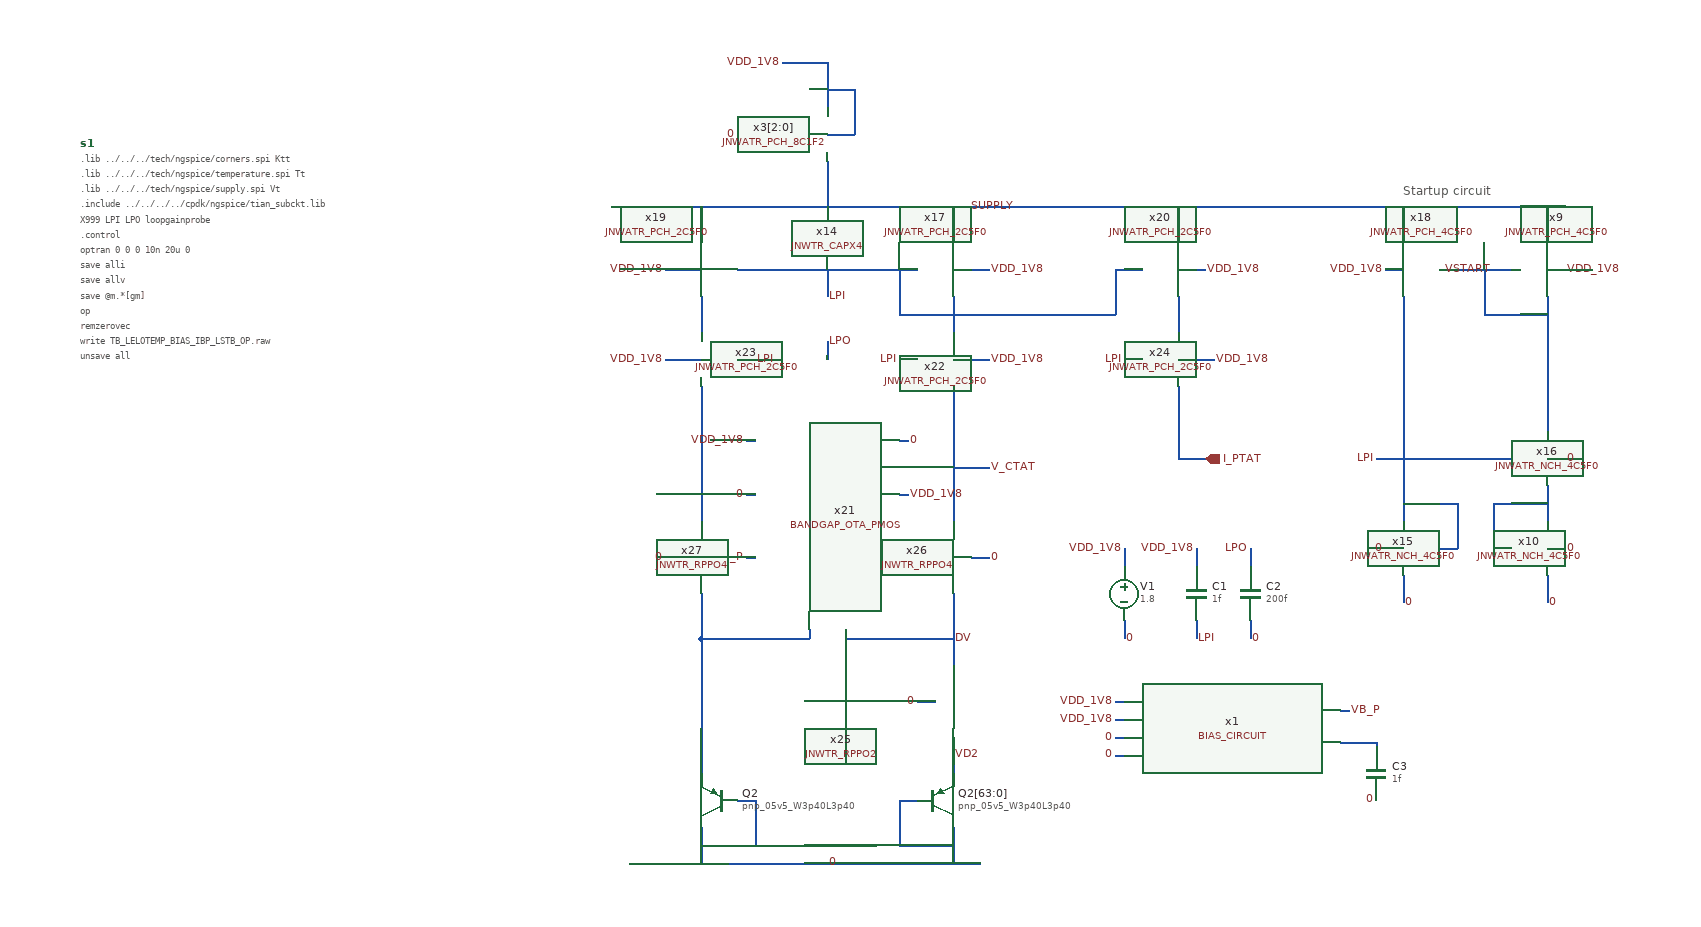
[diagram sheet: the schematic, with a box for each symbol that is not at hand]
v {xschem version=3.4.7 file_version=1.2}
G {}
K {}
V {}
S {}
E {}
B 2 790 -340 1590 60 {flags=graph

y2=71.09439
ypos1=0
ypos2=2
divy=5
subdivy=1
unity=1


divx=5
subdivx=8
xlabmag=1.0
ylabmag=1.0
node=re(lg_mag)
color=5
dataset=-1
unitx=1
logx=1
logy=0
sim_type=ac

y1=-47.074905
autoload=1
x1=2.1288585
x2=8.6859343}
B 2 790 70 1590 470 {flags=graph


ypos1=0
ypos2=2
divy=5
subdivy=4
unity=1

x2=8.6859343
divx=5
subdivx=8
xlabmag=1.0
ylabmag=1.0


dataset=-1
unitx=1
logx=1
logy=0
sim_type=ac
x1=2.1288585
y1=-242.0359
y2=16.778858
color=4
node=re(lg_phase)
autoload=0
rawfile=$netlist_dir/TB_LELOTEMP_BIAS_IBP_LSTB.raw}
T {Startup circuit} 520 -230 0 0 0.4 0.4 {}
N 210 180 210 200 {
lab=VDD_1V8}
N -220 -130 -20 -130 {lab=LPI}
N -140 270 -140 280 {lab=#net1}
N -260 280 -140 280 {lab=#net1}
N -100 270 -100 280 {lab=DV}
N 20 390 20 430 {lab=VD2}
N -260 280 -260 430 {lab=#net1}
N -40 510 20 510 {lab=0}
N -40 460 -40 510 {lab=0}
N -40 460 -20 460 {lab=0}
N 270 -130 300 -130 {lab=VDD_1V8}
N 200 -130 230 -130 {lab=LPI}
N 270 0 270 80 {lab=I_PTAT}
N -210 120 -200 120 {lab=0}
N -40 120 -30 120 {lab=VDD_1V8}
N 20 -130 60 -130 {lab=VDD_1V8}
N -300 -130 -260 -130 {lab=VDD_1V8}
N -260 -200 -260 -160 {lab=SUPPLY}
N 20 -200 20 -160 {lab=SUPPLY}
N 270 -200 270 -160 {lab=SUPPLY}
N 270 80 300 80 {lab=I_PTAT}
N 20 90 60 90 {lab=V_CTAT}
N -40 -130 -40 -80 {lab=LPI}
N 200 -130 200 -80 {lab=LPI}
N -120 -250 -120 -200 {lab=SUPPLY}
N -220 -280 -160 -280 {lab=0}
N -120 -360 -120 -310 {lab=VDD_1V8}
N -170 -360 -120 -360 {lab=VDD_1V8}
N -40 60 -30 60 {lab=0}
N -120 -280 -90 -280 {lab=VDD_1V8}
N -90 -330 -90 -280 {lab=VDD_1V8}
N -120 -330 -90 -330 {lab=VDD_1V8}
N -210 60 -200 60 {lab=VDD_1V8}
N -210 190 -200 190 {lab=VB_P}
N -300 -30 -260 -30 {lab=VDD_1V8}
N -220 -30 -200 -30 {lab=LPI}
N -260 -100 -260 -60 {lab=#net2}
N 20 -100 20 -60 {lab=#net3}
N 20 -30 60 -30 {lab=VDD_1V8}
N -40 -30 -20 -30 {lab=LPI}
N 270 -30 310 -30 {lab=VDD_1V8}
N 270 -100 270 -60 {lab=#net4}
N 210 -30 230 -30 {lab=LPI}
N -260 510 -200 510 {lab=0}
N -200 460 -200 510 {lab=0}
N -220 460 -200 460 {lab=0}
N -260 490 -260 530 {lab=0}
N 20 490 20 530 {lab=0}
N -40 -80 200 -80 {lab=LPI}
N 680 -200 680 -160 {lab=SUPPLY}
N 520 -200 520 -160 {lab=SUPPLY}
N 500 -130 520 -130 {lab=VDD_1V8}
N 680 -130 700 -130 {lab=VDD_1V8}
N 680 80 700 80 {lab=0}
N 560 -130 640 -130 {lab=VSTART}
N 610 -130 610 -80 {lab=VSTART}
N 610 -80 680 -80 {lab=VSTART}
N 620 180 640 180 {lab=#net5}
N 680 180 700 180 {lab=0}
N 620 130 620 180 {lab=#net5}
N 680 110 680 150 {lab=#net5}
N 620 130 680 130 {lab=#net5}
N 680 210 680 240 {lab=0}
N 560 180 580 180 {lab=LPI}
N 500 180 520 180 {lab=0}
N 580 130 580 180 {lab=LPI}
N 520 130 580 130 {lab=LPI}
N 520 210 520 240 {lab=0}
N 520 -100 520 150 {lab=LPI}
N 520 80 640 80 {lab=LPI}
N 680 -100 680 50 {lab=VSTART}
N 490 80 520 80 {lab=LPI}
N -100 280 20 280 {lab=DV}
N -220 -280 -160 -280 {lab=0}
N -20 350 0 350 {lab=0}
N -260 0 -260 110 {lab=#net6}
N 20 0 20 80 {lab=V_CTAT}
N 20 80 20 100 {lab=V_CTAT}
N 20 100 20 150 {lab=V_CTAT}
N 20 230 20 310 {lab=DV}
N -260 110 -260 150 {lab=#net6}
N -260 230 -260 280 {lab=#net1}
N 40 190 60 190 {lab=0}
N -300 190 -280 190 {lab=0}
N -360 -200 700 -200 {lab=SUPPLY}
N -340 530 50 530 {lab=0}
N 200 350 210 350 {lab=VDD_1V8}
N 200 370 210 370 {lab=VDD_1V8}
N 200 390 210 390 {lab=0}
N 200 410 210 410 {lab=0}
N 450 360 460 360 {lab=VB_P}
N 450 395 490 395 {lab=#net7}
N 490 395 490 400 {lab=#net7}
N -120 -50 -120 -30 {lab=LPO}
N -120 -130 -120 -100 {lab=LPI}
N 210 260 210 280 {lab=0}
N 350 180 350 200 {lab=LPO}
N 290 180 290 200 {lab=VDD_1V8}
N 290 260 290 280 {lab=LPI}
N 350 260 350 280 {lab=0}
C {devices/code_shown.sym} -949.3514969502943 -270 0 0 {name=s1 only_toplevel=false value="

.lib "../../../tech/ngspice/corners.spi" Ktt
.lib "../../../tech/ngspice/temperature.spi" Tt
.lib "../../../tech/ngspice/supply.spi" Vt
.include ../../../../cpdk/ngspice/tian_subckt.lib
X999 LPI LPO loopgainprobe

.control
optran 0 0 0 10n 20u 0
save alli
save allv
save @m.*[gm]
op
remzerovec
write TB_LELOTEMP_BIAS_IBP_LSTB_OP.raw
unsave all

save allv
save i(v1) i(v2)
* Set voltage AC to 1
ac dec 50 100 1G
* Set Current to 1
alter i.X999.Ii acmag=1
alter v.X999.Vi acmag=0
ac dec 50 100 1G
let lg_mag = db(tian_loop())
let lg_phase = 180*cph(-tian_loop())/pi
remzerovec
write TB_LELOTEMP_BIAS_IBP_LSTB.raw

meas ac gm_db find lg_mag when lg_phase=0
meas ac pm_deg find lg_phase when lg_mag=0
meas ac f3db when lg_phase=135
meas ac ug when lg_mag=0
meas ac lf_gain find lg_mag at=1k
remzerovec
write TB_LELOTEMP_BIAS_IBP_LSTB_meas.raw
exit
.endc
.end

"}
C {devices/vsource.sym} 210 230 0 0 {name=V1 value=1.8 savecurrent=false}
C {devices/lab_wire.sym} 210 180 0 0 {name=p6 sig_type=std_logic lab=VDD_1V8
value=1.8}
C {devices/capa.sym} 290 230 0 0 {name=C1
m=1
value=1f
footprint=1206
device="ceramic capacitor"}
C {devices/lab_wire.sym} 290 180 0 0 {name=p11 sig_type=std_logic lab=VDD_1V8}
C {devices/lab_wire.sym} 290 280 2 0 {name=p12 sig_type=std_logic lab=LPI}
C {devices/lab_wire.sym} -120 -100 2 0 {name=p1 sig_type=std_logic lab=LPI}
C {devices/lab_wire.sym} 350 180 0 0 {name=p2 sig_type=std_logic lab=LPO}
C {devices/capa.sym} 350 230 0 0 {name=C2
m=1
value=200f
footprint=1206
device="ceramic capacitor"}
C {devices/lab_wire.sym} 210 280 2 0 {name=p13 sig_type=std_logic lab=0
value=1.8}
C {devices/lab_wire.sym} 350 280 2 0 {name=p14 sig_type=std_logic lab=0
value=1.8}
C {devices/lab_pin.sym} 20 410 0 1 {name=p29 sig_type=std_logic lab=VD2}
C {devices/lab_pin.sym} 20 280 0 1 {name=p30 sig_type=std_logic lab=DV}
C {devices/opin.sym} 300 80 0 0 {name=p31 lab=I_PTAT}
C {sky130_fd_pr/pnp_05v5.sym} 0 460 0 0 {name=Q2[63:0]
model=pnp_05v5_W3p40L3p40
m=1
spiceprefix=X
}
C {devices/lab_wire.sym} -30 120 0 1 {name=p38 sig_type=std_logic lab=VDD_1V8}
C {devices/lab_wire.sym} -300 -130 0 0 {name=p39 sig_type=std_logic lab=VDD_1V8}
C {devices/lab_wire.sym} 60 -130 0 1 {name=p40 sig_type=std_logic lab=VDD_1V8}
C {devices/lab_wire.sym} 300 -130 0 1 {name=p41 sig_type=std_logic lab=VDD_1V8}
C {devices/lab_wire.sym} -210 190 0 0 {name=p45 sig_type=std_logic lab=VB_P}
C {devices/lab_wire.sym} -300 -30 0 0 {name=p46 sig_type=std_logic lab=VDD_1V8}
C {devices/lab_wire.sym} 60 -30 0 1 {name=p48 sig_type=std_logic lab=VDD_1V8}
C {devices/lab_wire.sym} 310 -30 0 1 {name=p50 sig_type=std_logic lab=VDD_1V8}
C {sky130_fd_pr/pnp_05v5.sym} -240 460 0 1 {name=Q2
model=pnp_05v5_W3p40L3p40
m=1
spiceprefix=X
}
C {JNW_ATR_SKY130A/JNWATR_NCH_4C5F0.sym} 640 80 0 0 {name=x16}
C {JNW_ATR_SKY130A/JNWATR_PCH_4C5F0.sym} 560 -130 0 1 {name=x18}
C {devices/lab_wire.sym} 500 -130 0 0 {name=p51 sig_type=std_logic lab=VDD_1V8}
C {devices/lab_wire.sym} 700 -130 0 1 {name=p52 sig_type=std_logic lab=VDD_1V8}
C {JNW_ATR_SKY130A/JNWATR_PCH_4C5F0.sym} 640 -130 0 0 {name=x9}
C {JNW_ATR_SKY130A/JNWATR_NCH_4C5F0.sym} 640 180 0 0 {name=x10}
C {JNW_ATR_SKY130A/JNWATR_NCH_4C5F0.sym} 560 180 0 1 {name=x15}
C {JNW_TR_SKY130A/JNWTR_CAPX4.sym} -120 -140 0 0 {name=x14 }
C {devices/lab_wire.sym} 620 -130 0 0 {name=p61 sig_type=std_logic lab=VSTART}
C {LELO_GR03_SKY130A/BANDGAP_OTA_PMOS.sym} -100 120 1 1 {name=x21}
C {JNW_ATR_SKY130A/JNWATR_PCH_2C5F0.sym} -20 -130 0 0 {name=x17}
C {JNW_ATR_SKY130A/JNWATR_PCH_2C5F0.sym} -220 -130 0 1 {name=x19}
C {JNW_ATR_SKY130A/JNWATR_PCH_2C5F0.sym} 230 -130 0 0 {name=x20 }
C {JNW_ATR_SKY130A/JNWATR_PCH_8C1F2.sym} -160 -280 0 0 {name=x3[2:0]}
C {JNW_ATR_SKY130A/JNWATR_PCH_2C5F0.sym} -20 -30 0 0 {name=x22}
C {JNW_ATR_SKY130A/JNWATR_PCH_2C5F0.sym} -220 -30 0 1 {name=x23}
C {JNW_ATR_SKY130A/JNWATR_PCH_2C5F0.sym} 230 -30 0 0 {name=x24}
C {JNW_TR_SKY130A/JNWTR_RPPO2.sym} 20 310 1 0 {name=x25 }
C {devices/lab_wire.sym} 90 -200 0 0 {name=p63 sig_type=std_logic lab=SUPPLY}
C {JNW_TR_SKY130A/JNWTR_RPPO4.sym} 20 230 3 0 {name=x26 }
C {JNW_TR_SKY130A/JNWTR_RPPO4.sym} -260 150 1 0 {name=x27 }
C {devices/lab_wire.sym} -120 530 2 0 {name=p66 sig_type=std_logic lab=0
value=1.8}
C {devices/lab_wire.sym} -20 350 2 1 {name=p62 sig_type=std_logic lab=0
value=1.8}
C {devices/lab_wire.sym} 60 190 2 0 {name=p64 sig_type=std_logic lab=0
value=1.8}
C {devices/lab_wire.sym} -210 120 2 1 {name=p17 sig_type=std_logic lab=0
value=1.8}
C {devices/lab_wire.sym} -300 190 2 1 {name=p65 sig_type=std_logic lab=0
value=1.8}
C {devices/lab_wire.sym} 500 180 2 1 {name=p56 sig_type=std_logic lab=0
value=1.8}
C {devices/lab_wire.sym} 520 240 2 0 {name=p57 sig_type=std_logic lab=0
value=1.8}
C {devices/lab_wire.sym} 680 240 2 0 {name=p55 sig_type=std_logic lab=0
value=1.8}
C {devices/lab_wire.sym} 700 180 2 0 {name=p67 sig_type=std_logic lab=0
value=1.8}
C {devices/lab_wire.sym} 700 80 2 0 {name=p53 sig_type=std_logic lab=0
value=1.8}
C {devices/lab_wire.sym} -170 -360 0 0 {name=p33 sig_type=std_logic lab=VDD_1V8}
C {devices/lab_pin.sym} 60 90 0 1 {name=p32 sig_type=std_logic lab=V_CTAT}
C {LELO_GR03_SKY130A/BIAS_CIRCUIT.sym} 360 380 0 0 {name=x1}
C {devices/lab_wire.sym} 200 350 0 0 {name=p3 sig_type=std_logic lab=VDD_1V8
value=1.8}
C {devices/lab_wire.sym} -210 60 0 0 {name=p4 sig_type=std_logic lab=VDD_1V8}
C {devices/lab_wire.sym} -30 60 0 1 {name=p8 sig_type=std_logic lab=0
value=1.8}
C {devices/lab_wire.sym} -220 -280 2 1 {name=p9 sig_type=std_logic lab=0
value=1.8}
C {devices/lab_wire.sym} 200 370 0 0 {name=p15 sig_type=std_logic lab=VDD_1V8
value=1.8}
C {devices/lab_wire.sym} 200 390 0 0 {name=p16 sig_type=std_logic lab=0
value=1.8}
C {devices/lab_wire.sym} 200 410 0 0 {name=p18 sig_type=std_logic lab=0
value=1.8}
C {devices/lab_wire.sym} 460 360 0 1 {name=p19 sig_type=std_logic lab=VB_P}
C {devices/lab_wire.sym} 490 460 2 1 {name=p20 sig_type=std_logic lab=0
value=1.8}
C {devices/capa.sym} 490 430 0 0 {name=C3
m=1
value=1f
footprint=1206
device="ceramic capacitor"}
C {devices/lab_wire.sym} -120 -50 0 1 {name=p21 sig_type=std_logic lab=LPO}
C {devices/lab_wire.sym} -200 -30 0 1 {name=p7 sig_type=std_logic lab=LPI}
C {devices/lab_wire.sym} -40 -30 0 0 {name=p22 sig_type=std_logic lab=LPI}
C {devices/lab_wire.sym} 210 -30 0 0 {name=p23 sig_type=std_logic lab=LPI}
C {devices/lab_wire.sym} 490 80 0 0 {name=p24 sig_type=std_logic lab=LPI}
